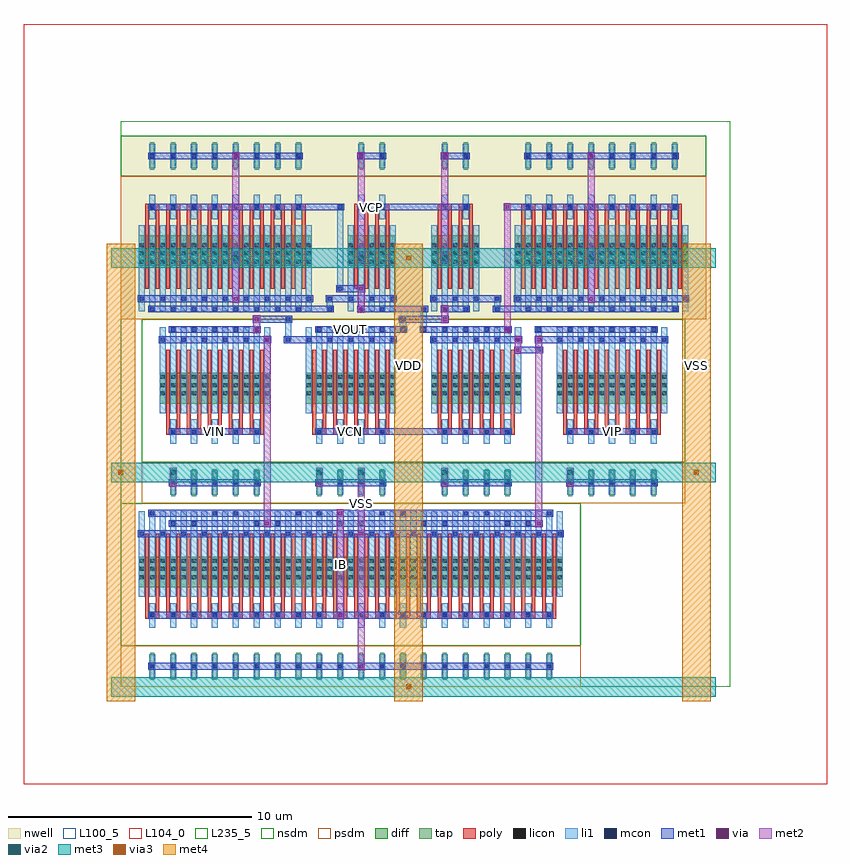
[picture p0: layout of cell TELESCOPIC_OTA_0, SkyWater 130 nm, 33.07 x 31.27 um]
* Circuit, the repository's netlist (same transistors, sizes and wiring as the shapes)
* NGSPICE file created from TELESCOPIC_OTA_0.ext - technology: sky130A

.subckt PMOS_S_77937488_X8_Y1_1774869395 a_230_441# a_200_252# w_0_0#
X0 w_0_0# a_200_252# a_230_441# w_0_0# sky130_fd_pr__pfet_01v8 ad=0.1764 pd=1.54 as=0.1764 ps=1.54 w=1.26 l=0.15 M=16
.ends

.subckt PMOS_4T_36899923_X2_Y1_1774869394 a_230_441# a_200_252# a_147_441# w_0_0#
X0 a_147_441# a_200_252# a_230_441# w_0_0# sky130_fd_pr__pfet_01v8 ad=0.1764 pd=1.54 as=0.1764 ps=1.54 w=1.26 l=0.15 M=4
.ends

.subckt NMOS_4T_27824333_X5_Y1_1774869392 a_230_441# a_200_252# a_147_441# a_241_1232#
X0 a_147_441# a_200_252# a_230_441# a_241_1232# sky130_fd_pr__nfet_01v8 ad=0.3339 pd=3.05 as=0.1764 ps=1.54 w=1.26 l=0.15 M=10
.ends

.subckt NMOS_4T_50719370_X4_Y1_1774869393 a_230_441# a_200_252# a_147_441# a_241_1232#
X0 a_230_441# a_200_252# a_147_441# a_241_1232# sky130_fd_pr__nfet_01v8 ad=0.1764 pd=1.54 as=0.3339 ps=3.05 w=1.26 l=0.15 M=8
.ends

.subckt SCM_NMOS_14227459_X10_Y1_1774869396 a_402_441# a_200_252# a_147_441#
X0 a_147_441# a_200_252# a_200_252# a_147_441# sky130_fd_pr__nfet_01v8 ad=0.1764 pd=1.54 as=0.1764 ps=1.54 w=1.26 l=0.15 M=20
X1 a_147_441# a_200_252# a_402_441# a_147_441# sky130_fd_pr__nfet_01v8 ad=0.1764 pd=1.54 as=0.1764 ps=1.54 w=1.26 l=0.15 M=20
.ends

.subckt TELESCOPIC_OTA_0 IB VCN VOUT VIP VIN VCP VSS VDD
XPMOS_S_77937488_X8_Y1_1774869395_0 li_3071_3091# m1_3150_2912# VDD PMOS_S_77937488_X8_Y1_1774869395
XPMOS_S_77937488_X8_Y1_1774869395_1 li_1695_3091# m1_3150_2912# VDD PMOS_S_77937488_X8_Y1_1774869395
XPMOS_4T_36899923_X2_Y1_1774869394_0 VOUT VCP li_3071_3091# VDD PMOS_4T_36899923_X2_Y1_1774869394
XPMOS_4T_36899923_X2_Y1_1774869394_1 m1_3150_2912# VCP li_1695_3091# VDD PMOS_4T_36899923_X2_Y1_1774869394
XNMOS_4T_27824333_X5_Y1_1774869392_0 li_1351_2839# VIN m1_3354_1316# VSS NMOS_4T_27824333_X5_Y1_1774869392
XNMOS_4T_27824333_X5_Y1_1774869392_1 li_3415_2755# VIP m1_3354_1316# VSS NMOS_4T_27824333_X5_Y1_1774869392
XNMOS_4T_50719370_X4_Y1_1774869393_0 VOUT VCN li_1351_2839# VSS NMOS_4T_50719370_X4_Y1_1774869393
XNMOS_4T_50719370_X4_Y1_1774869393_1 m1_3150_2912# VCN li_3415_2755# VSS NMOS_4T_50719370_X4_Y1_1774869393
XSCM_NMOS_14227459_X10_Y1_1774869396_0 m1_3354_1316# IB VSS SCM_NMOS_14227459_X10_Y1_1774869396
.ends

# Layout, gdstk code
from math import pi, radians
import gdstk
lib = gdstk.Library(unit=1e-6, precision=1e-09)
def R(c, l, rs):  # rectangles x0, y0, x1, y1
    for r in rs: c.add(gdstk.rectangle(r[:2], r[2:], *l))
def A(c, l, x, y, w, h, nx, ny, dx, dy):  # array of equal rectangles
    R(c, l, [(x+i*dx, y+j*dy, x+i*dx+w, y+j*dy+h) for i in range(nx) for j in range(ny)])
def P(c, l, *ps):  # polygons
    for p in ps: c.add(gdstk.Polygon(p, *l))
nwell = (64, 20)
diff = (65, 20)
tap = (65, 44)
poly = (66, 20)
licon = (66, 44)
li1 = (67, 20)
mcon = (67, 44)
met1 = (68, 20)
via = (68, 44)
met2 = (69, 20)
via2 = (69, 44)
met3 = (70, 20)
via3 = (70, 44)
met4 = (71, 20)
nsdm = (93, 44)
psdm = (94, 20)
L100_5 = (100, 5)
L104_0 = (104, 0)
L235_5 = (235, 5)

scm_nmos_14227459_x10_y1 = lib.new_cell('SCM_NMOS_14227459_X10_Y1_1774869396')
R(scm_nmos_14227459_x10_y1, diff, [(0.735,2.205,18.185,3.465)])
A(scm_nmos_14227459_x10_y1, tap, 1.205, 6.16, 0.17, 1.12, 20, 1, 0.86, 0)
A(scm_nmos_14227459_x10_y1, poly, 1, 1.26, 0.15, 3.36, 40, 1, 0.43, 0)
A(scm_nmos_14227459_x10_y1, poly, 1, 4.485, 0.58, 0.27, 20, 1, 0.86, 0)
A(scm_nmos_14227459_x10_y1, licon, 0.775, 2.285, 0.17, 0.17, 3, 3, 0.43, 0.34)
A(scm_nmos_14227459_x10_y1, licon, 1.635, 2.285, 0.17, 0.17, 3, 3, 0.43, 0.34)
A(scm_nmos_14227459_x10_y1, licon, 2.495, 2.285, 0.17, 0.17, 3, 3, 0.43, 0.34)
A(scm_nmos_14227459_x10_y1, licon, 3.355, 2.285, 0.17, 0.17, 3, 3, 0.43, 0.34)
A(scm_nmos_14227459_x10_y1, licon, 4.215, 2.285, 0.17, 0.17, 3, 3, 0.43, 0.34)
A(scm_nmos_14227459_x10_y1, licon, 5.075, 2.285, 0.17, 0.17, 3, 3, 0.43, 0.34)
A(scm_nmos_14227459_x10_y1, licon, 5.935, 2.285, 0.17, 0.17, 3, 3, 0.43, 0.34)
A(scm_nmos_14227459_x10_y1, licon, 6.795, 2.285, 0.17, 0.17, 3, 3, 0.43, 0.34)
A(scm_nmos_14227459_x10_y1, licon, 7.655, 2.285, 0.17, 0.17, 3, 3, 0.43, 0.34)
A(scm_nmos_14227459_x10_y1, licon, 8.515, 2.285, 0.17, 0.17, 3, 3, 0.43, 0.34)
A(scm_nmos_14227459_x10_y1, licon, 9.375, 2.285, 0.17, 0.17, 3, 3, 0.43, 0.34)
A(scm_nmos_14227459_x10_y1, licon, 10.235, 2.285, 0.17, 0.17, 3, 3, 0.43, 0.34)
A(scm_nmos_14227459_x10_y1, licon, 11.095, 2.285, 0.17, 0.17, 3, 3, 0.43, 0.34)
A(scm_nmos_14227459_x10_y1, licon, 11.955, 2.285, 0.17, 0.17, 3, 3, 0.43, 0.34)
A(scm_nmos_14227459_x10_y1, licon, 12.815, 2.285, 0.17, 0.17, 3, 3, 0.43, 0.34)
A(scm_nmos_14227459_x10_y1, licon, 13.675, 2.285, 0.17, 0.17, 3, 3, 0.43, 0.34)
A(scm_nmos_14227459_x10_y1, licon, 14.535, 2.285, 0.17, 0.17, 3, 3, 0.43, 0.34)
A(scm_nmos_14227459_x10_y1, licon, 15.395, 2.285, 0.17, 0.17, 3, 3, 0.43, 0.34)
A(scm_nmos_14227459_x10_y1, licon, 16.255, 2.285, 0.17, 0.17, 3, 3, 0.43, 0.34)
A(scm_nmos_14227459_x10_y1, licon, 17.115, 2.285, 0.17, 0.17, 3, 3, 0.43, 0.34)
A(scm_nmos_14227459_x10_y1, licon, 1.205, 4.535, 0.17, 0.17, 20, 2, 0.86, 2.1)
A(scm_nmos_14227459_x10_y1, li1, 0.735, 0.335, 0.25, 3.53, 41, 1, 0.43, 0)
A(scm_nmos_14227459_x10_y1, li1, 1.165, 4.115, 0.25, 1.01, 20, 2, 0.86, 2.1)
A(scm_nmos_14227459_x10_y1, mcon, 0.775, 1.175, 0.17, 0.17, 21, 1, 0.86, 0)
A(scm_nmos_14227459_x10_y1, mcon, 1.205, 4.535, 0.17, 0.17, 20, 2, 0.86, 2.1)
R(scm_nmos_14227459_x10_y1, mcon, [(1.205,0.335,1.375,0.505), (3.785,0.335,3.955,0.505), (4.645,0.335,4.815,0.505), (7.225,0.335,7.395,0.505), (8.085,0.335,8.255,0.505), (10.665,0.335,10.835,0.505), (11.525,0.335,11.695,0.505), (14.105,0.335,14.275,0.505), (14.965,0.335,15.135,0.505), (17.545,0.335,17.715,0.505), (2.065,0.755,2.235,0.925), (2.925,0.755,3.095,0.925), (5.505,0.755,5.675,0.925), (6.365,0.755,6.535,0.925), (8.945,0.755,9.115,0.925), (9.805,0.755,9.975,0.925), (12.385,0.755,12.555,0.925), (13.245,0.755,13.415,0.925), (15.825,0.755,15.995,0.925), (16.685,0.755,16.855,0.925)])
R(scm_nmos_14227459_x10_y1, met1, [(1.12,0.28,17.8,0.56), (1.98,0.7,16.94,0.98), (0.69,1.12,18.23,1.4), (1.12,4.48,17.8,4.76), (1.12,6.58,17.8,6.86)])
R(scm_nmos_14227459_x10_y1, via, [(8.955,0.345,9.105,0.495), (9.815,1.185,9.965,1.335), (8.955,4.545,9.105,4.695), (9.815,6.645,9.965,6.795)])
R(scm_nmos_14227459_x10_y1, met2, [(8.89,0.26,9.17,4.78), (9.75,1.1,10.03,6.88)])
R(scm_nmos_14227459_x10_y1, nsdm, [(0,0,18.92,5.88)])
R(scm_nmos_14227459_x10_y1, psdm, [(0,5.88,18.92,7.56)])
R(scm_nmos_14227459_x10_y1, L100_5, [(0,0,18.92,7.56)])

pmos_s_77937488_x8_y1_17 = lib.new_cell('PMOS_S_77937488_X8_Y1_1774869395')
R(pmos_s_77937488_x8_y1_17, nwell, [(0,0,8.6,7.56)])
R(pmos_s_77937488_x8_y1_17, diff, [(0.735,2.205,7.865,3.465)])
A(pmos_s_77937488_x8_y1_17, tap, 1.205, 6.16, 0.17, 1.12, 8, 1, 0.86, 0)
A(pmos_s_77937488_x8_y1_17, poly, 1, 1.26, 0.15, 3.36, 16, 1, 0.43, 0)
A(pmos_s_77937488_x8_y1_17, poly, 1, 4.485, 0.58, 0.27, 8, 1, 0.86, 0)
A(pmos_s_77937488_x8_y1_17, licon, 0.775, 2.285, 0.17, 0.17, 3, 3, 0.43, 0.34)
A(pmos_s_77937488_x8_y1_17, licon, 1.635, 2.285, 0.17, 0.17, 3, 3, 0.43, 0.34)
A(pmos_s_77937488_x8_y1_17, licon, 2.495, 2.285, 0.17, 0.17, 3, 3, 0.43, 0.34)
A(pmos_s_77937488_x8_y1_17, licon, 3.355, 2.285, 0.17, 0.17, 3, 3, 0.43, 0.34)
A(pmos_s_77937488_x8_y1_17, licon, 4.215, 2.285, 0.17, 0.17, 3, 3, 0.43, 0.34)
A(pmos_s_77937488_x8_y1_17, licon, 5.075, 2.285, 0.17, 0.17, 3, 3, 0.43, 0.34)
A(pmos_s_77937488_x8_y1_17, licon, 5.935, 2.285, 0.17, 0.17, 3, 3, 0.43, 0.34)
A(pmos_s_77937488_x8_y1_17, licon, 6.795, 2.285, 0.17, 0.17, 3, 3, 0.43, 0.34)
A(pmos_s_77937488_x8_y1_17, licon, 1.205, 4.535, 0.17, 0.17, 8, 2, 0.86, 2.1)
A(pmos_s_77937488_x8_y1_17, li1, 0.735, 0.335, 0.25, 3.53, 17, 1, 0.43, 0)
A(pmos_s_77937488_x8_y1_17, li1, 1.165, 4.115, 0.25, 1.01, 8, 2, 0.86, 2.1)
A(pmos_s_77937488_x8_y1_17, mcon, 1.205, 0.335, 0.17, 0.17, 8, 2, 0.86, 4.2)
A(pmos_s_77937488_x8_y1_17, mcon, 0.775, 0.755, 0.17, 0.17, 9, 1, 0.86, 0)
A(pmos_s_77937488_x8_y1_17, mcon, 1.205, 6.635, 0.17, 0.17, 8, 1, 0.86, 0)
R(pmos_s_77937488_x8_y1_17, met1, [(1.12,0.28,7.48,0.56), (0.69,0.7,7.91,0.98), (1.12,4.48,7.48,4.76), (1.12,6.58,7.48,6.86)])
R(pmos_s_77937488_x8_y1_17, via, [(4.655,0.765,4.805,0.915), (4.655,6.645,4.805,6.795)])
R(pmos_s_77937488_x8_y1_17, met2, [(4.59,0.68,4.87,6.88)])
R(pmos_s_77937488_x8_y1_17, nsdm, [(0,5.88,8.6,7.56)])
R(pmos_s_77937488_x8_y1_17, psdm, [(0,0,8.6,5.88)])
R(pmos_s_77937488_x8_y1_17, L100_5, [(0,0,8.6,7.56)])

nmos_4t_50719370_x4_y1_1 = lib.new_cell('NMOS_4T_50719370_X4_Y1_1774869393')
R(nmos_4t_50719370_x4_y1_1, diff, [(0.735,2.205,4.425,3.465)])
A(nmos_4t_50719370_x4_y1_1, tap, 1.205, 6.16, 0.17, 1.12, 4, 1, 0.86, 0)
A(nmos_4t_50719370_x4_y1_1, poly, 1, 1.26, 0.15, 3.36, 8, 1, 0.43, 0)
A(nmos_4t_50719370_x4_y1_1, poly, 1, 4.485, 0.58, 0.27, 4, 1, 0.86, 0)
A(nmos_4t_50719370_x4_y1_1, licon, 0.775, 2.285, 0.17, 0.17, 3, 3, 0.43, 0.34)
A(nmos_4t_50719370_x4_y1_1, licon, 1.635, 2.285, 0.17, 0.17, 3, 3, 0.43, 0.34)
A(nmos_4t_50719370_x4_y1_1, licon, 2.495, 2.285, 0.17, 0.17, 3, 3, 0.43, 0.34)
A(nmos_4t_50719370_x4_y1_1, licon, 3.355, 2.285, 0.17, 0.17, 3, 3, 0.43, 0.34)
A(nmos_4t_50719370_x4_y1_1, licon, 1.205, 4.535, 0.17, 0.17, 4, 2, 0.86, 2.1)
A(nmos_4t_50719370_x4_y1_1, li1, 0.735, 0.335, 0.25, 3.53, 9, 1, 0.43, 0)
A(nmos_4t_50719370_x4_y1_1, li1, 1.165, 4.115, 0.25, 1.01, 4, 2, 0.86, 2.1)
A(nmos_4t_50719370_x4_y1_1, mcon, 1.205, 0.335, 0.17, 0.17, 4, 2, 0.86, 4.2)
A(nmos_4t_50719370_x4_y1_1, mcon, 0.775, 0.755, 0.17, 0.17, 5, 1, 0.86, 0)
A(nmos_4t_50719370_x4_y1_1, mcon, 1.205, 6.635, 0.17, 0.17, 4, 1, 0.86, 0)
R(nmos_4t_50719370_x4_y1_1, met1, [(1.12,0.28,4.04,0.56), (0.69,0.7,4.47,0.98), (1.12,4.48,4.04,4.76), (1.12,6.58,4.04,6.86)])
R(nmos_4t_50719370_x4_y1_1, nsdm, [(0,0,5.16,5.88)])
R(nmos_4t_50719370_x4_y1_1, psdm, [(0,5.88,5.16,7.56)])
R(nmos_4t_50719370_x4_y1_1, L100_5, [(0,0,5.16,7.56)])

nmos_4t_27824333_x5_y1_1 = lib.new_cell('NMOS_4T_27824333_X5_Y1_1774869392')
R(nmos_4t_27824333_x5_y1_1, diff, [(0.735,2.205,5.285,3.465)])
A(nmos_4t_27824333_x5_y1_1, tap, 1.205, 6.16, 0.17, 1.12, 5, 1, 0.86, 0)
A(nmos_4t_27824333_x5_y1_1, poly, 1, 1.26, 0.15, 3.36, 10, 1, 0.43, 0)
A(nmos_4t_27824333_x5_y1_1, poly, 1, 4.485, 0.58, 0.27, 5, 1, 0.86, 0)
A(nmos_4t_27824333_x5_y1_1, licon, 0.775, 2.285, 0.17, 0.17, 3, 3, 0.43, 0.34)
A(nmos_4t_27824333_x5_y1_1, licon, 1.635, 2.285, 0.17, 0.17, 3, 3, 0.43, 0.34)
A(nmos_4t_27824333_x5_y1_1, licon, 2.495, 2.285, 0.17, 0.17, 3, 3, 0.43, 0.34)
A(nmos_4t_27824333_x5_y1_1, licon, 3.355, 2.285, 0.17, 0.17, 3, 3, 0.43, 0.34)
A(nmos_4t_27824333_x5_y1_1, licon, 4.215, 2.285, 0.17, 0.17, 3, 3, 0.43, 0.34)
A(nmos_4t_27824333_x5_y1_1, licon, 1.205, 4.535, 0.17, 0.17, 5, 2, 0.86, 2.1)
A(nmos_4t_27824333_x5_y1_1, li1, 0.735, 0.335, 0.25, 3.53, 11, 1, 0.43, 0)
A(nmos_4t_27824333_x5_y1_1, li1, 1.165, 4.115, 0.25, 1.01, 5, 2, 0.86, 2.1)
A(nmos_4t_27824333_x5_y1_1, mcon, 1.205, 0.335, 0.17, 0.17, 5, 2, 0.86, 4.2)
A(nmos_4t_27824333_x5_y1_1, mcon, 0.775, 0.755, 0.17, 0.17, 6, 1, 0.86, 0)
A(nmos_4t_27824333_x5_y1_1, mcon, 1.205, 6.635, 0.17, 0.17, 5, 1, 0.86, 0)
R(nmos_4t_27824333_x5_y1_1, met1, [(1.12,0.28,4.9,0.56), (0.69,0.7,5.33,0.98), (1.12,4.48,4.9,4.76), (1.12,6.58,4.9,6.86)])
R(nmos_4t_27824333_x5_y1_1, nsdm, [(0,0,6.02,5.88)])
R(nmos_4t_27824333_x5_y1_1, psdm, [(0,5.88,6.02,7.56)])
R(nmos_4t_27824333_x5_y1_1, L100_5, [(0,0,6.02,7.56)])

pmos_4t_36899923_x2_y1_1 = lib.new_cell('PMOS_4T_36899923_X2_Y1_1774869394')
R(pmos_4t_36899923_x2_y1_1, nwell, [(0,0,3.44,7.56)])
R(pmos_4t_36899923_x2_y1_1, diff, [(0.735,2.205,2.705,3.465)])
R(pmos_4t_36899923_x2_y1_1, tap, [(1.205,6.16,1.375,7.28), (2.065,6.16,2.235,7.28)])
A(pmos_4t_36899923_x2_y1_1, poly, 1, 1.26, 0.15, 3.36, 4, 1, 0.43, 0)
R(pmos_4t_36899923_x2_y1_1, poly, [(1,4.485,1.58,4.755), (1.86,4.485,2.44,4.755)])
A(pmos_4t_36899923_x2_y1_1, licon, 0.775, 2.285, 0.17, 0.17, 3, 3, 0.43, 0.34)
A(pmos_4t_36899923_x2_y1_1, licon, 1.635, 2.285, 0.17, 0.17, 3, 3, 0.43, 0.34)
R(pmos_4t_36899923_x2_y1_1, licon, [(1.205,4.535,1.375,4.705), (2.065,4.535,2.235,4.705), (1.205,6.635,1.375,6.805), (2.065,6.635,2.235,6.805)])
A(pmos_4t_36899923_x2_y1_1, li1, 0.735, 0.335, 0.25, 3.53, 5, 1, 0.43, 0)
R(pmos_4t_36899923_x2_y1_1, li1, [(1.165,4.115,1.415,5.125), (2.025,4.115,2.275,5.125), (1.165,6.215,1.415,7.225), (2.025,6.215,2.275,7.225)])
A(pmos_4t_36899923_x2_y1_1, mcon, 0.775, 0.755, 0.17, 0.17, 3, 1, 0.86, 0)
R(pmos_4t_36899923_x2_y1_1, mcon, [(1.205,0.335,1.375,0.505), (2.065,0.335,2.235,0.505), (1.205,4.535,1.375,4.705), (2.065,4.535,2.235,4.705), (1.205,6.635,1.375,6.805), (2.065,6.635,2.235,6.805)])
R(pmos_4t_36899923_x2_y1_1, met1, [(1.12,0.28,2.32,0.56), (0.69,0.7,2.75,0.98), (1.12,4.48,2.32,4.76), (1.12,6.58,2.32,6.86)])
R(pmos_4t_36899923_x2_y1_1, nsdm, [(0,5.88,3.44,7.56)])
R(pmos_4t_36899923_x2_y1_1, psdm, [(0,0,3.44,5.88)])
R(pmos_4t_36899923_x2_y1_1, L100_5, [(0,0,3.44,7.56)])

telescopic_ota_0 = lib.new_cell('TELESCOPIC_OTA_0')
R(telescopic_ota_0, li1, [(17.075,13.775,17.325,13.945), (17.075,13.775,17.325,13.945), (17.075,13.86,17.325,14.7), (6.755,14.195,7.005,14.365), (6.755,14.195,7.005,14.365), (6.755,14.28,7.005,15.12), (11.485,14.615,11.735,14.785), (11.485,14.615,11.735,14.785), (12.345,14.615,12.595,14.785), (12.345,14.615,12.595,14.785), (12.345,14.615,12.595,14.785), (12.345,14.615,12.595,14.785), (17.075,14.615,17.325,14.785), (17.075,14.615,17.325,14.785), (11.485,14.7,11.735,15.12), (12.345,14.7,12.595,15.54), (6.755,15.035,7.005,15.205), (6.755,15.035,7.005,15.205), (11.485,15.035,11.735,15.205), (11.485,15.035,11.735,15.205), (8.475,15.455,8.725,15.625), (8.475,15.455,8.725,15.625), (12.345,15.455,12.595,15.625), (12.345,15.455,12.595,15.625), (12.345,15.455,12.595,15.625), (12.345,15.455,12.595,15.625), (15.355,15.455,15.605,15.625), (15.355,15.455,15.605,15.625), (8.475,15.54,8.725,15.96), (15.355,15.54,15.605,15.96), (8.475,15.875,8.725,16.045), (8.475,15.875,8.725,16.045), (15.355,15.875,15.605,16.045), (15.355,15.875,15.605,16.045), (8.905,16.295,9.155,16.465), (8.905,16.295,9.155,16.465), (8.905,16.295,9.155,16.465), (8.905,16.295,9.155,16.465), (8.905,16.295,9.155,16.465), (8.905,16.295,9.155,16.465), (8.905,16.38,9.155,19.74), (8.905,19.655,9.155,19.825), (8.905,19.655,9.155,19.825), (8.905,19.655,9.155,19.825), (8.905,19.655,9.155,19.825), (8.905,19.655,9.155,19.825), (8.905,19.655,9.155,19.825)])
R(telescopic_ota_0, mcon, [(17.115,13.775,17.285,13.945), (17.115,13.775,17.285,13.945), (6.795,14.195,6.965,14.365), (6.795,14.195,6.965,14.365), (11.525,14.615,11.695,14.785), (11.525,14.615,11.695,14.785), (12.385,14.615,12.555,14.785), (12.385,14.615,12.555,14.785), (12.385,14.615,12.555,14.785), (12.385,14.615,12.555,14.785), (17.115,14.615,17.285,14.785), (17.115,14.615,17.285,14.785), (6.795,15.035,6.965,15.205), (6.795,15.035,6.965,15.205), (11.525,15.035,11.695,15.205), (11.525,15.035,11.695,15.205), (8.515,15.455,8.685,15.625), (8.515,15.455,8.685,15.625), (12.385,15.455,12.555,15.625), (12.385,15.455,12.555,15.625), (12.385,15.455,12.555,15.625), (12.385,15.455,12.555,15.625), (15.395,15.455,15.565,15.625), (15.395,15.455,15.565,15.625), (8.515,15.875,8.685,16.045), (8.515,15.875,8.685,16.045), (15.395,15.875,15.565,16.045), (15.395,15.875,15.565,16.045), (8.945,16.295,9.115,16.465), (8.945,16.295,9.115,16.465), (8.945,16.295,9.115,16.465), (8.945,16.295,9.115,16.465), (8.945,16.295,9.115,16.465), (8.945,16.295,9.115,16.465), (8.945,19.655,9.115,19.825), (8.945,19.655,9.115,19.825), (8.945,19.655,9.115,19.825), (8.945,19.655,9.115,19.825), (8.945,19.655,9.115,19.825), (8.945,19.655,9.115,19.825)])
R(telescopic_ota_0, met1, [(5.86,6.58,6.18,6.86), (5.86,6.58,6.18,6.86), (5.86,6.58,6.18,6.86), (5.86,6.58,6.18,6.86), (16.77,6.58,17.2,6.86), (17.04,6.58,17.36,6.86), (17.04,6.58,17.36,6.86), (1.99,8.26,2.31,8.54), (1.99,8.26,2.31,8.54), (8.01,8.26,8.33,8.54), (8.01,8.26,8.33,8.54), (8.01,8.26,8.33,8.54), (8.01,8.26,8.33,8.54), (13.17,8.26,13.49,8.54), (13.17,8.26,13.49,8.54), (13.17,8.26,13.49,8.54), (13.17,8.26,13.49,8.54), (13.17,8.26,13.49,8.54), (18.33,8.26,18.65,8.54), (18.33,8.26,18.65,8.54), (18.33,8.26,18.65,8.54), (10.75,10.36,13.33,10.64), (16.18,13.72,16.5,14), (16.18,13.72,16.5,14), (16.34,13.72,17.2,14), (17.03,13.72,17.37,14), (17.03,13.72,17.37,14), (5.86,14.14,6.18,14.42), (5.86,14.14,6.18,14.42), (5.86,14.14,6.18,14.42), (5.86,14.14,6.18,14.42), (6.71,14.14,7.05,14.42), (6.71,14.14,7.05,14.42), (6.88,14.14,7.74,14.42), (16.18,14.14,16.5,14.42), (16.18,14.14,16.5,14.42), (17.04,14.14,17.36,14.42), (17.04,14.14,17.36,14.42), (17.2,14.14,18.06,14.42), (5.43,14.56,5.75,14.84), (5.43,14.56,5.75,14.84), (10.75,14.56,11.61,14.84), (11.44,14.56,11.78,14.84), (11.44,14.56,11.78,14.84), (12.3,14.56,12.64,14.84), (12.3,14.56,12.64,14.84), (12.3,14.56,12.64,14.84), (12.3,14.56,12.64,14.84), (12.47,14.56,13.33,14.84), (15.75,14.56,16.07,14.84), (15.75,14.56,16.07,14.84), (17.03,14.56,17.37,14.84), (17.03,14.56,17.37,14.84), (17.2,14.56,18.49,14.84), (5.43,14.98,5.75,15.26), (5.43,14.98,5.75,15.26), (5.59,14.98,6.88,15.26), (6.71,14.98,7.05,15.26), (6.71,14.98,7.05,15.26), (11.44,14.98,11.78,15.26), (11.44,14.98,11.78,15.26), (11.61,14.98,13.33,15.26), (13.17,14.98,13.49,15.26), (13.17,14.98,13.49,15.26), (7.31,15.4,8.6,15.68), (8.43,15.4,8.77,15.68), (8.43,15.4,8.77,15.68), (9.73,15.4,10.05,15.68), (9.73,15.4,10.05,15.68), (9.73,15.4,10.05,15.68), (9.73,15.4,10.05,15.68), (9.73,15.4,10.05,15.68), (9.73,15.4,10.05,15.68), (10.75,15.4,12.47,15.68), (12.3,15.4,12.64,15.68), (12.3,15.4,12.64,15.68), (12.3,15.4,12.64,15.68), (12.3,15.4,12.64,15.68), (13.17,15.4,13.49,15.68), (13.17,15.4,13.49,15.68), (15.31,15.4,15.65,15.68), (15.31,15.4,15.65,15.68), (15.48,15.4,16.77,15.68), (8.43,15.82,8.77,16.1), (8.43,15.82,8.77,16.1), (8.6,15.82,9.46,16.1), (14.62,15.82,15.48,16.1), (15.31,15.82,15.65,16.1), (15.31,15.82,15.65,16.1), (8.86,16.24,9.2,16.52), (8.86,16.24,9.2,16.52), (8.86,16.24,9.2,16.52), (8.86,16.24,9.2,16.52), (8.86,16.24,9.2,16.52), (8.86,16.24,9.2,16.52), (9.03,16.24,9.89,16.52), (9.73,16.24,10.05,16.52), (9.73,16.24,10.05,16.52), (9.73,16.24,10.05,16.52), (9.73,16.24,10.05,16.52), (9.73,16.24,10.05,16.52), (9.73,16.24,10.05,16.52), (7.31,19.6,9.03,19.88), (8.86,19.6,9.2,19.88), (8.86,19.6,9.2,19.88), (8.86,19.6,9.2,19.88), (8.86,19.6,9.2,19.88), (8.86,19.6,9.2,19.88), (8.86,19.6,9.2,19.88), (10.75,19.6,13.33,19.88), (15.75,19.6,16.07,19.88), (15.75,19.6,16.07,19.88), (15.91,19.6,16.77,19.88), (9.73,21.7,10.05,21.98), (9.73,21.7,10.05,21.98), (9.73,21.7,10.05,21.98), (13.17,21.7,13.49,21.98), (13.17,21.7,13.49,21.98)])
P(telescopic_ota_0, met1, [(0,0),(0,0),(0,0),(0,0)],
  [(0,0),(0,0),(0,0),(0,0)],
  [(0,0),(0,0),(0,0),(0,0)],
  [(0,0),(0,0),(0,0),(0,0)],
  [(0,0),(0,0),(0,0),(0,0)],
  [(0,0),(0,0),(0,0),(0,0)],
  [(0,0),(0,0),(0,0),(0,0)],
  [(0,0),(0,0),(0,0),(0,0)],
  [(0,0),(0,0),(0,0),(0,0)],
  [(0,0),(0,0),(0,0),(0,0)],
  [(0,0),(0,0),(0,0),(0,0)],
  [(0,0),(0,0),(0,0),(0,0)],
  [(0,0),(0,0),(0,0),(0,0)],
  [(0,0),(0,0),(0,0),(0,0)],
  [(0,0),(0,0),(0,0),(0,0)],
  [(0,0),(0,0),(0,0),(0,0)],
  [(0,0),(0,0),(0,0),(0,0)],
  [(0,0),(0,0),(0,0),(0,0)],
  [(0,0),(0,0),(0,0),(0,0)],
  [(0,0),(0,0),(0,0),(0,0)],
  [(0,0),(0,0),(0,0),(0,0)],
  [(0,0),(0,0),(0,0),(0,0)],
  [(0,0),(0,0),(0,0),(0,0)],
  [(0,0),(0,0),(0,0),(0,0)],
  [(0,0),(0,0),(0,0),(0,0)],
  [(0,0),(0,0),(0,0),(0,0)],
  [(0,0),(0,0),(0,0),(0,0)],
  [(0,0),(0,0),(0,0),(0,0)],
  [(0,0),(0,0),(0,0),(0,0)],
  [(0,0),(0,0),(0,0),(0,0)],
  [(0,0),(0,0),(0,0),(0,0)],
  [(0,0),(0,0),(0,0),(0,0)],
  [(0,0),(0,0),(0,0),(0,0)],
  [(0,0),(0,0),(0,0),(0,0)])
R(telescopic_ota_0, via, [(5.945,6.645,6.095,6.795), (5.945,6.645,6.095,6.795), (5.945,6.645,6.095,6.795), (5.945,6.645,6.095,6.795), (17.125,6.645,17.275,6.795), (17.125,6.645,17.275,6.795), (2.075,8.325,2.225,8.475), (2.075,8.325,2.225,8.475), (8.095,8.325,8.245,8.475), (8.095,8.325,8.245,8.475), (8.095,8.325,8.245,8.475), (8.095,8.325,8.245,8.475), (13.255,8.325,13.405,8.475), (13.255,8.325,13.405,8.475), (13.255,8.325,13.405,8.475), (13.255,8.325,13.405,8.475), (13.255,8.325,13.405,8.475), (18.415,8.325,18.565,8.475), (18.415,8.325,18.565,8.475), (18.415,8.325,18.565,8.475), (16.265,13.785,16.415,13.935), (16.265,13.785,16.415,13.935), (5.945,14.205,6.095,14.355), (5.945,14.205,6.095,14.355), (5.945,14.205,6.095,14.355), (5.945,14.205,6.095,14.355), (16.265,14.205,16.415,14.355), (16.265,14.205,16.415,14.355), (17.125,14.205,17.275,14.355), (17.125,14.205,17.275,14.355), (5.515,14.625,5.665,14.775), (5.515,14.625,5.665,14.775), (15.835,14.625,15.985,14.775), (15.835,14.625,15.985,14.775), (5.515,15.045,5.665,15.195), (5.515,15.045,5.665,15.195), (13.255,15.045,13.405,15.195), (13.255,15.045,13.405,15.195), (9.815,15.465,9.965,15.615), (9.815,15.465,9.965,15.615), (9.815,15.465,9.965,15.615), (9.815,15.465,9.965,15.615), (9.815,15.465,9.965,15.615), (9.815,15.465,9.965,15.615), (13.255,15.465,13.405,15.615), (13.255,15.465,13.405,15.615), (9.815,16.305,9.965,16.455), (9.815,16.305,9.965,16.455), (9.815,16.305,9.965,16.455), (9.815,16.305,9.965,16.455), (9.815,16.305,9.965,16.455), (9.815,16.305,9.965,16.455), (15.835,19.665,15.985,19.815), (15.835,19.665,15.985,19.815), (9.815,21.765,9.965,21.915), (9.815,21.765,9.965,21.915), (9.815,21.765,9.965,21.915), (13.255,21.765,13.405,21.915), (13.255,21.765,13.405,21.915)])
A(telescopic_ota_0, met2, 8.03, 8.4, 0.28, 0.42, 3, 1, 5.16, 0)
R(telescopic_ota_0, met2, [(9.75,6.3,10.03,8.82), (5.88,6.56,6.16,6.88), (5.88,6.56,6.16,6.88), (5.88,6.56,6.16,6.88), (5.88,6.56,6.16,6.88), (17.06,6.56,17.34,6.88), (17.06,6.56,17.34,6.88), (5.88,6.72,6.16,14.28), (17.06,6.72,17.34,14.28), (2.01,8.24,2.29,8.56), (2.01,8.24,2.29,8.56), (8.03,8.24,8.31,8.56), (8.03,8.24,8.31,8.56), (8.03,8.24,8.31,8.56), (8.03,8.24,8.31,8.56), (13.19,8.24,13.47,8.56), (13.19,8.24,13.47,8.56), (13.19,8.24,13.47,8.56), (13.19,8.24,13.47,8.56), (13.19,8.24,13.47,8.56), (18.35,8.24,18.63,8.56), (18.35,8.24,18.63,8.56), (18.35,8.24,18.63,8.56), (2.01,8.4,2.29,8.82), (2.01,8.635,2.29,9.005), (2.01,8.635,2.29,9.005), (8.03,8.635,8.31,9.005), (8.03,8.635,8.31,9.005), (8.03,8.635,8.31,9.005), (8.03,8.635,8.31,9.005), (9.75,8.635,10.03,9.005), (9.75,8.635,10.03,9.005), (9.75,8.635,10.03,9.005), (9.75,8.635,10.03,9.005), (9.75,8.635,10.03,9.005), (9.75,8.635,10.03,9.005), (13.19,8.635,13.47,9.005), (13.19,8.635,13.47,9.005), (13.19,8.635,13.47,9.005), (13.19,8.635,13.47,9.005), (13.19,8.635,13.47,9.005), (18.35,8.635,18.63,9.005), (18.35,8.635,18.63,9.005), (18.35,8.635,18.63,9.005), (16.2,13.7,16.48,14.02), (16.2,13.7,16.48,14.02), (16.2,13.86,16.48,14.28), (5.88,14.12,6.16,14.44), (5.88,14.12,6.16,14.44), (5.88,14.12,6.16,14.44), (5.88,14.12,6.16,14.44), (16.2,14.12,16.48,14.44), (16.2,14.12,16.48,14.44), (17.06,14.12,17.34,14.44), (17.06,14.12,17.34,14.44), (5.45,14.54,5.73,14.86), (5.45,14.54,5.73,14.86), (15.77,14.54,16.05,14.86), (15.77,14.54,16.05,14.86), (5.45,14.7,5.73,15.12), (15.77,14.7,16.05,19.74), (5.45,14.96,5.73,15.28), (5.45,14.96,5.73,15.28), (13.19,14.96,13.47,15.28), (13.19,14.96,13.47,15.28), (13.19,15.12,13.47,15.54), (9.75,15.38,10.03,15.7), (9.75,15.38,10.03,15.7), (9.75,15.38,10.03,15.7), (9.75,15.38,10.03,15.7), (9.75,15.38,10.03,15.7), (9.75,15.38,10.03,15.7), (13.19,15.38,13.47,15.7), (13.19,15.38,13.47,15.7), (9.75,15.54,10.03,16.38), (9.75,16.22,10.03,16.54), (9.75,16.22,10.03,16.54), (9.75,16.22,10.03,16.54), (9.75,16.22,10.03,16.54), (9.75,16.22,10.03,16.54), (9.75,16.22,10.03,16.54), (4.59,17.455,4.87,17.825), (4.59,17.455,4.87,17.825), (4.59,17.455,4.87,17.825), (4.59,17.455,4.87,17.825), (4.59,17.455,4.87,17.825), (9.75,17.455,10.03,17.825), (9.75,17.455,10.03,17.825), (9.75,17.455,10.03,17.825), (13.19,17.455,13.47,17.825), (13.19,17.455,13.47,17.825), (19.21,17.455,19.49,17.825), (19.21,17.455,19.49,17.825), (19.21,17.455,19.49,17.825), (19.21,17.455,19.49,17.825), (9.75,17.64,10.03,21.84), (13.19,17.64,13.47,21.84), (15.77,19.58,16.05,19.9), (15.77,19.58,16.05,19.9), (9.75,21.68,10.03,22), (9.75,21.68,10.03,22), (9.75,21.68,10.03,22), (13.19,21.68,13.47,22), (13.19,21.68,13.47,22)])
P(telescopic_ota_0, met2, [(0,0),(0,0),(0,0),(0,0)],
  [(0,0),(0,0),(0,0),(0,0)],
  [(0,0),(0,0),(0,0),(0,0)],
  [(0,0),(0,0),(0,0),(0,0)],
  [(0,0),(0,0),(0,0),(0,0)])
R(telescopic_ota_0, via2, [(2.05,8.72,2.25,8.92), (2.05,8.72,2.25,8.92), (8.07,8.72,8.27,8.92), (8.07,8.72,8.27,8.92), (8.07,8.72,8.27,8.92), (8.07,8.72,8.27,8.92), (9.79,8.72,9.99,8.92), (9.79,8.72,9.99,8.92), (9.79,8.72,9.99,8.92), (9.79,8.72,9.99,8.92), (9.79,8.72,9.99,8.92), (9.79,8.72,9.99,8.92), (13.23,8.72,13.43,8.92), (13.23,8.72,13.43,8.92), (13.23,8.72,13.43,8.92), (13.23,8.72,13.43,8.92), (13.23,8.72,13.43,8.92), (18.39,8.72,18.59,8.92), (18.39,8.72,18.59,8.92), (18.39,8.72,18.59,8.92), (4.63,17.54,4.83,17.74), (4.63,17.54,4.83,17.74), (4.63,17.54,4.83,17.74), (4.63,17.54,4.83,17.74), (4.63,17.54,4.83,17.74), (9.79,17.54,9.99,17.74), (9.79,17.54,9.99,17.74), (9.79,17.54,9.99,17.74), (13.23,17.54,13.43,17.74), (13.23,17.54,13.43,17.74), (19.25,17.54,19.45,17.74), (19.25,17.54,19.45,17.74), (19.25,17.54,19.45,17.74), (19.25,17.54,19.45,17.74)])
A(telescopic_ota_0, met3, -0.4, -0.4, 4.24, 0.8, 3, 3, 3.44, 8.82)
A(telescopic_ota_0, met3, 9.92, -0.4, 2.32, 0.8, 1, 3, 0, 8.82)
A(telescopic_ota_0, met3, 11.44, -0.4, 2.72, 0.8, 1, 3, 0, 8.82)
A(telescopic_ota_0, met3, 13.36, -0.4, 4.24, 0.8, 1, 3, 0, 8.82)
A(telescopic_ota_0, met3, 16.8, -0.4, 4.24, 0.8, 1, 3, 0, 8.82)
A(telescopic_ota_0, met3, 20.24, -0.4, 3.84, 0.8, 1, 3, 0, 8.82)
A(telescopic_ota_0, met3, 23.28, -0.4, 1.2, 0.8, 1, 3, 0, 8.82)
R(telescopic_ota_0, met3, [(11.675,-0.4,12.005,0.4), (-0.165,8.42,0.165,9.22), (1.985,8.42,2.315,9.22), (1.985,8.42,2.315,9.22), (8.005,8.42,8.335,9.22), (8.005,8.42,8.335,9.22), (8.005,8.42,8.335,9.22), (8.005,8.42,8.335,9.22), (9.725,8.42,10.055,9.22), (9.725,8.42,10.055,9.22), (9.725,8.42,10.055,9.22), (9.725,8.42,10.055,9.22), (9.725,8.42,10.055,9.22), (9.725,8.42,10.055,9.22), (13.165,8.42,13.495,9.22), (13.165,8.42,13.495,9.22), (13.165,8.42,13.495,9.22), (13.165,8.42,13.495,9.22), (13.165,8.42,13.495,9.22), (18.325,8.42,18.655,9.22), (18.325,8.42,18.655,9.22), (18.325,8.42,18.655,9.22), (23.515,8.42,23.845,9.22), (4.565,17.24,4.895,18.04), (4.565,17.24,4.895,18.04), (4.565,17.24,4.895,18.04), (4.565,17.24,4.895,18.04), (4.565,17.24,4.895,18.04), (9.725,17.24,10.055,18.04), (9.725,17.24,10.055,18.04), (9.725,17.24,10.055,18.04), (11.675,17.24,12.005,18.04), (13.165,17.24,13.495,18.04), (13.165,17.24,13.495,18.04), (19.185,17.24,19.515,18.04), (19.185,17.24,19.515,18.04), (19.185,17.24,19.515,18.04), (19.185,17.24,19.515,18.04)])
R(telescopic_ota_0, via3, [(11.74,-0.1,11.94,0.1), (-0.1,8.72,0.1,8.92), (23.58,8.72,23.78,8.92), (11.74,17.54,11.94,17.74)])
A(telescopic_ota_0, met4, -0.59, -0.59, 1.18, 10, 3, 2, 11.84, 8.82)
R(telescopic_ota_0, met4, [(11.25,-0.165,12.43,0.165), (-0.59,8.655,0.59,8.985), (23.09,8.655,24.27,8.985), (11.25,17.475,12.43,17.805)])
R(telescopic_ota_0, L104_0, [(-4,-4,29.07,27.27)])
R(telescopic_ota_0, L235_5, [(0,0,25.07,23.27)])
telescopic_ota_0.add(gdstk.Reference(scm_nmos_14227459_x10_y1, (0,7.56), x_reflection=True))
telescopic_ota_0.add(gdstk.Reference(pmos_s_77937488_x8_y1_17, (0,15.12)))
telescopic_ota_0.add(gdstk.Reference(pmos_s_77937488_x8_y1_17, (24.08,15.12), rotation=pi, x_reflection=True))
telescopic_ota_0.add(gdstk.Reference(nmos_4t_50719370_x4_y1_1, (17.2,15.12), rotation=pi))
telescopic_ota_0.add(gdstk.Reference(nmos_4t_50719370_x4_y1_1, (6.88,15.12), x_reflection=True))
telescopic_ota_0.add(gdstk.Reference(nmos_4t_27824333_x5_y1_1, (23.22,15.12), rotation=pi))
telescopic_ota_0.add(gdstk.Reference(nmos_4t_27824333_x5_y1_1, (0.86,15.12), x_reflection=True))
telescopic_ota_0.add(gdstk.Reference(pmos_4t_36899923_x2_y1_1, (8.6,15.12)))
telescopic_ota_0.add(gdstk.Reference(pmos_4t_36899923_x2_y1_1, (15.48,15.12), rotation=pi, x_reflection=True))
telescopic_ota_0.add(gdstk.Label('IB', (9.03,5.04), layer=69, texttype=5))
telescopic_ota_0.add(gdstk.Label('VCN', (9.46,10.5), layer=68, texttype=5))
telescopic_ota_0.add(gdstk.Label('VOUT', (9.46,14.7), layer=68, texttype=5))
telescopic_ota_0.add(gdstk.Label('VIP', (20.21,10.5), layer=68, texttype=5))
telescopic_ota_0.add(gdstk.Label('VIN', (3.87,10.5), layer=68, texttype=5))
telescopic_ota_0.add(gdstk.Label('VCP', (10.32,19.74), layer=68, texttype=5))
telescopic_ota_0.add(gdstk.Label('VSS', (9.89,7.56), layer=69, texttype=5))
telescopic_ota_0.add(gdstk.Label('VSS', (23.68,13.23), layer=71, texttype=5))
telescopic_ota_0.add(gdstk.Label('VSS', (23.68,13.23), layer=71, texttype=5))
telescopic_ota_0.add(gdstk.Label('VSS', (23.68,13.23), layer=71, texttype=5))
telescopic_ota_0.add(gdstk.Label('VSS', (23.68,13.23), layer=71, texttype=5))
telescopic_ota_0.add(gdstk.Label('VSS', (23.68,13.23), layer=71, texttype=5))
telescopic_ota_0.add(gdstk.Label('VSS', (23.68,13.23), layer=71, texttype=5))
telescopic_ota_0.add(gdstk.Label('VSS', (23.68,13.23), layer=71, texttype=5))
telescopic_ota_0.add(gdstk.Label('VSS', (23.68,13.23), layer=71, texttype=5))
telescopic_ota_0.add(gdstk.Label('VSS', (23.68,13.23), layer=71, texttype=5))
telescopic_ota_0.add(gdstk.Label('VSS', (23.68,13.23), layer=71, texttype=5))
telescopic_ota_0.add(gdstk.Label('VSS', (23.68,13.23), layer=71, texttype=5))
telescopic_ota_0.add(gdstk.Label('VSS', (23.68,13.23), layer=71, texttype=5))
telescopic_ota_0.add(gdstk.Label('VSS', (23.68,13.23), layer=71, texttype=5))
telescopic_ota_0.add(gdstk.Label('VSS', (23.68,13.23), layer=71, texttype=5))
telescopic_ota_0.add(gdstk.Label('VDD', (11.84,13.23), layer=71, texttype=5))
telescopic_ota_0.add(gdstk.Label('VDD', (11.84,13.23), layer=71, texttype=5))
telescopic_ota_0.add(gdstk.Label('VDD', (11.84,13.23), layer=71, texttype=5))
telescopic_ota_0.add(gdstk.Label('VDD', (11.84,13.23), layer=71, texttype=5))
telescopic_ota_0.add(gdstk.Label('VDD', (11.84,13.23), layer=71, texttype=5))
telescopic_ota_0.add(gdstk.Label('VDD', (9.89,19.74), layer=69, texttype=5))
telescopic_ota_0.add(gdstk.Label('VDD', (11.84,13.23), layer=71, texttype=5))
telescopic_ota_0.add(gdstk.Label('VDD', (11.84,13.23), layer=71, texttype=5))
telescopic_ota_0.add(gdstk.Label('VDD', (11.84,13.23), layer=71, texttype=5))
telescopic_ota_0.add(gdstk.Label('VDD', (11.84,13.23), layer=71, texttype=5))
telescopic_ota_0.add(gdstk.Label('VDD', (11.84,13.23), layer=71, texttype=5))

lib.write_gds('TELESCOPIC_OTA_0.gds')
